# Generated by FakeRAM 2.0
VERSION 5.7 ;
BUSBITCHARS "[]" ;
PROPERTYDEFINITIONS
  MACRO width INTEGER ;
  MACRO depth INTEGER ;
  MACRO banks INTEGER ;
END PROPERTYDEFINITIONS
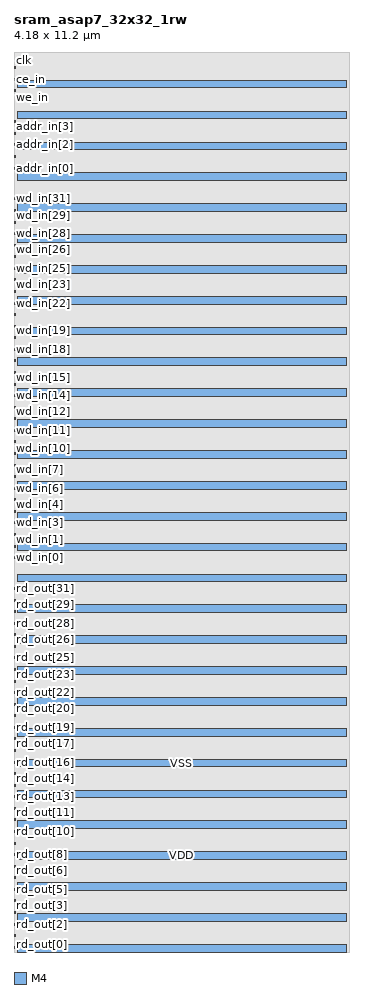
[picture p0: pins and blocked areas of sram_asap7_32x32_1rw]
MACRO sram_asap7_32x32_1rw
  PROPERTY width 32 ;
  PROPERTY depth 32 ;
  PROPERTY banks 1 ;
  FOREIGN sram_asap7_32x32_1rw 0 0 ;
  SYMMETRY X Y R90 ;
  SIZE 4.180 BY 11.200 ;
  CLASS BLOCK ;
  PIN rd_out[0]
    DIRECTION OUTPUT ;
    USE SIGNAL ;
    SHAPE ABUTMENT ;
    PORT
      LAYER M4 ;
      RECT 0.000 0.048 0.024 0.072 ;
    END
  END rd_out[0]
  PIN rd_out[1]
    DIRECTION OUTPUT ;
    USE SIGNAL ;
    SHAPE ABUTMENT ;
    PORT
      LAYER M4 ;
      RECT 0.000 0.192 0.024 0.216 ;
    END
  END rd_out[1]
  PIN rd_out[2]
    DIRECTION OUTPUT ;
    USE SIGNAL ;
    SHAPE ABUTMENT ;
    PORT
      LAYER M4 ;
      RECT 0.000 0.336 0.024 0.360 ;
    END
  END rd_out[2]
  PIN rd_out[3]
    DIRECTION OUTPUT ;
    USE SIGNAL ;
    SHAPE ABUTMENT ;
    PORT
      LAYER M4 ;
      RECT 0.000 0.480 0.024 0.504 ;
    END
  END rd_out[3]
  PIN rd_out[4]
    DIRECTION OUTPUT ;
    USE SIGNAL ;
    SHAPE ABUTMENT ;
    PORT
      LAYER M4 ;
      RECT 0.000 0.624 0.024 0.648 ;
    END
  END rd_out[4]
  PIN rd_out[5]
    DIRECTION OUTPUT ;
    USE SIGNAL ;
    SHAPE ABUTMENT ;
    PORT
      LAYER M4 ;
      RECT 0.000 0.768 0.024 0.792 ;
    END
  END rd_out[5]
  PIN rd_out[6]
    DIRECTION OUTPUT ;
    USE SIGNAL ;
    SHAPE ABUTMENT ;
    PORT
      LAYER M4 ;
      RECT 0.000 0.912 0.024 0.936 ;
    END
  END rd_out[6]
  PIN rd_out[7]
    DIRECTION OUTPUT ;
    USE SIGNAL ;
    SHAPE ABUTMENT ;
    PORT
      LAYER M4 ;
      RECT 0.000 1.056 0.024 1.080 ;
    END
  END rd_out[7]
  PIN rd_out[8]
    DIRECTION OUTPUT ;
    USE SIGNAL ;
    SHAPE ABUTMENT ;
    PORT
      LAYER M4 ;
      RECT 0.000 1.200 0.024 1.224 ;
    END
  END rd_out[8]
  PIN rd_out[9]
    DIRECTION OUTPUT ;
    USE SIGNAL ;
    SHAPE ABUTMENT ;
    PORT
      LAYER M4 ;
      RECT 0.000 1.344 0.024 1.368 ;
    END
  END rd_out[9]
  PIN rd_out[10]
    DIRECTION OUTPUT ;
    USE SIGNAL ;
    SHAPE ABUTMENT ;
    PORT
      LAYER M4 ;
      RECT 0.000 1.488 0.024 1.512 ;
    END
  END rd_out[10]
  PIN rd_out[11]
    DIRECTION OUTPUT ;
    USE SIGNAL ;
    SHAPE ABUTMENT ;
    PORT
      LAYER M4 ;
      RECT 0.000 1.632 0.024 1.656 ;
    END
  END rd_out[11]
  PIN rd_out[12]
    DIRECTION OUTPUT ;
    USE SIGNAL ;
    SHAPE ABUTMENT ;
    PORT
      LAYER M4 ;
      RECT 0.000 1.776 0.024 1.800 ;
    END
  END rd_out[12]
  PIN rd_out[13]
    DIRECTION OUTPUT ;
    USE SIGNAL ;
    SHAPE ABUTMENT ;
    PORT
      LAYER M4 ;
      RECT 0.000 1.920 0.024 1.944 ;
    END
  END rd_out[13]
  PIN rd_out[14]
    DIRECTION OUTPUT ;
    USE SIGNAL ;
    SHAPE ABUTMENT ;
    PORT
      LAYER M4 ;
      RECT 0.000 2.064 0.024 2.088 ;
    END
  END rd_out[14]
  PIN rd_out[15]
    DIRECTION OUTPUT ;
    USE SIGNAL ;
    SHAPE ABUTMENT ;
    PORT
      LAYER M4 ;
      RECT 0.000 2.208 0.024 2.232 ;
    END
  END rd_out[15]
  PIN rd_out[16]
    DIRECTION OUTPUT ;
    USE SIGNAL ;
    SHAPE ABUTMENT ;
    PORT
      LAYER M4 ;
      RECT 0.000 2.352 0.024 2.376 ;
    END
  END rd_out[16]
  PIN rd_out[17]
    DIRECTION OUTPUT ;
    USE SIGNAL ;
    SHAPE ABUTMENT ;
    PORT
      LAYER M4 ;
      RECT 0.000 2.496 0.024 2.520 ;
    END
  END rd_out[17]
  PIN rd_out[18]
    DIRECTION OUTPUT ;
    USE SIGNAL ;
    SHAPE ABUTMENT ;
    PORT
      LAYER M4 ;
      RECT 0.000 2.640 0.024 2.664 ;
    END
  END rd_out[18]
  PIN rd_out[19]
    DIRECTION OUTPUT ;
    USE SIGNAL ;
    SHAPE ABUTMENT ;
    PORT
      LAYER M4 ;
      RECT 0.000 2.784 0.024 2.808 ;
    END
  END rd_out[19]
  PIN rd_out[20]
    DIRECTION OUTPUT ;
    USE SIGNAL ;
    SHAPE ABUTMENT ;
    PORT
      LAYER M4 ;
      RECT 0.000 2.928 0.024 2.952 ;
    END
  END rd_out[20]
  PIN rd_out[21]
    DIRECTION OUTPUT ;
    USE SIGNAL ;
    SHAPE ABUTMENT ;
    PORT
      LAYER M4 ;
      RECT 0.000 3.072 0.024 3.096 ;
    END
  END rd_out[21]
  PIN rd_out[22]
    DIRECTION OUTPUT ;
    USE SIGNAL ;
    SHAPE ABUTMENT ;
    PORT
      LAYER M4 ;
      RECT 0.000 3.216 0.024 3.240 ;
    END
  END rd_out[22]
  PIN rd_out[23]
    DIRECTION OUTPUT ;
    USE SIGNAL ;
    SHAPE ABUTMENT ;
    PORT
      LAYER M4 ;
      RECT 0.000 3.360 0.024 3.384 ;
    END
  END rd_out[23]
  PIN rd_out[24]
    DIRECTION OUTPUT ;
    USE SIGNAL ;
    SHAPE ABUTMENT ;
    PORT
      LAYER M4 ;
      RECT 0.000 3.504 0.024 3.528 ;
    END
  END rd_out[24]
  PIN rd_out[25]
    DIRECTION OUTPUT ;
    USE SIGNAL ;
    SHAPE ABUTMENT ;
    PORT
      LAYER M4 ;
      RECT 0.000 3.648 0.024 3.672 ;
    END
  END rd_out[25]
  PIN rd_out[26]
    DIRECTION OUTPUT ;
    USE SIGNAL ;
    SHAPE ABUTMENT ;
    PORT
      LAYER M4 ;
      RECT 0.000 3.792 0.024 3.816 ;
    END
  END rd_out[26]
  PIN rd_out[27]
    DIRECTION OUTPUT ;
    USE SIGNAL ;
    SHAPE ABUTMENT ;
    PORT
      LAYER M4 ;
      RECT 0.000 3.936 0.024 3.960 ;
    END
  END rd_out[27]
  PIN rd_out[28]
    DIRECTION OUTPUT ;
    USE SIGNAL ;
    SHAPE ABUTMENT ;
    PORT
      LAYER M4 ;
      RECT 0.000 4.080 0.024 4.104 ;
    END
  END rd_out[28]
  PIN rd_out[29]
    DIRECTION OUTPUT ;
    USE SIGNAL ;
    SHAPE ABUTMENT ;
    PORT
      LAYER M4 ;
      RECT 0.000 4.224 0.024 4.248 ;
    END
  END rd_out[29]
  PIN rd_out[30]
    DIRECTION OUTPUT ;
    USE SIGNAL ;
    SHAPE ABUTMENT ;
    PORT
      LAYER M4 ;
      RECT 0.000 4.368 0.024 4.392 ;
    END
  END rd_out[30]
  PIN rd_out[31]
    DIRECTION OUTPUT ;
    USE SIGNAL ;
    SHAPE ABUTMENT ;
    PORT
      LAYER M4 ;
      RECT 0.000 4.512 0.024 4.536 ;
    END
  END rd_out[31]
  PIN wd_in[0]
    DIRECTION INPUT ;
    USE SIGNAL ;
    SHAPE ABUTMENT ;
    PORT
      LAYER M4 ;
      RECT 0.000 4.896 0.024 4.920 ;
    END
  END wd_in[0]
  PIN wd_in[1]
    DIRECTION INPUT ;
    USE SIGNAL ;
    SHAPE ABUTMENT ;
    PORT
      LAYER M4 ;
      RECT 0.000 5.040 0.024 5.064 ;
    END
  END wd_in[1]
  PIN wd_in[2]
    DIRECTION INPUT ;
    USE SIGNAL ;
    SHAPE ABUTMENT ;
    PORT
      LAYER M4 ;
      RECT 0.000 5.184 0.024 5.208 ;
    END
  END wd_in[2]
  PIN wd_in[3]
    DIRECTION INPUT ;
    USE SIGNAL ;
    SHAPE ABUTMENT ;
    PORT
      LAYER M4 ;
      RECT 0.000 5.328 0.024 5.352 ;
    END
  END wd_in[3]
  PIN wd_in[4]
    DIRECTION INPUT ;
    USE SIGNAL ;
    SHAPE ABUTMENT ;
    PORT
      LAYER M4 ;
      RECT 0.000 5.472 0.024 5.496 ;
    END
  END wd_in[4]
  PIN wd_in[5]
    DIRECTION INPUT ;
    USE SIGNAL ;
    SHAPE ABUTMENT ;
    PORT
      LAYER M4 ;
      RECT 0.000 5.616 0.024 5.640 ;
    END
  END wd_in[5]
  PIN wd_in[6]
    DIRECTION INPUT ;
    USE SIGNAL ;
    SHAPE ABUTMENT ;
    PORT
      LAYER M4 ;
      RECT 0.000 5.760 0.024 5.784 ;
    END
  END wd_in[6]
  PIN wd_in[7]
    DIRECTION INPUT ;
    USE SIGNAL ;
    SHAPE ABUTMENT ;
    PORT
      LAYER M4 ;
      RECT 0.000 5.904 0.024 5.928 ;
    END
  END wd_in[7]
  PIN wd_in[8]
    DIRECTION INPUT ;
    USE SIGNAL ;
    SHAPE ABUTMENT ;
    PORT
      LAYER M4 ;
      RECT 0.000 6.048 0.024 6.072 ;
    END
  END wd_in[8]
  PIN wd_in[9]
    DIRECTION INPUT ;
    USE SIGNAL ;
    SHAPE ABUTMENT ;
    PORT
      LAYER M4 ;
      RECT 0.000 6.192 0.024 6.216 ;
    END
  END wd_in[9]
  PIN wd_in[10]
    DIRECTION INPUT ;
    USE SIGNAL ;
    SHAPE ABUTMENT ;
    PORT
      LAYER M4 ;
      RECT 0.000 6.336 0.024 6.360 ;
    END
  END wd_in[10]
  PIN wd_in[11]
    DIRECTION INPUT ;
    USE SIGNAL ;
    SHAPE ABUTMENT ;
    PORT
      LAYER M4 ;
      RECT 0.000 6.480 0.024 6.504 ;
    END
  END wd_in[11]
  PIN wd_in[12]
    DIRECTION INPUT ;
    USE SIGNAL ;
    SHAPE ABUTMENT ;
    PORT
      LAYER M4 ;
      RECT 0.000 6.624 0.024 6.648 ;
    END
  END wd_in[12]
  PIN wd_in[13]
    DIRECTION INPUT ;
    USE SIGNAL ;
    SHAPE ABUTMENT ;
    PORT
      LAYER M4 ;
      RECT 0.000 6.768 0.024 6.792 ;
    END
  END wd_in[13]
  PIN wd_in[14]
    DIRECTION INPUT ;
    USE SIGNAL ;
    SHAPE ABUTMENT ;
    PORT
      LAYER M4 ;
      RECT 0.000 6.912 0.024 6.936 ;
    END
  END wd_in[14]
  PIN wd_in[15]
    DIRECTION INPUT ;
    USE SIGNAL ;
    SHAPE ABUTMENT ;
    PORT
      LAYER M4 ;
      RECT 0.000 7.056 0.024 7.080 ;
    END
  END wd_in[15]
  PIN wd_in[16]
    DIRECTION INPUT ;
    USE SIGNAL ;
    SHAPE ABUTMENT ;
    PORT
      LAYER M4 ;
      RECT 0.000 7.200 0.024 7.224 ;
    END
  END wd_in[16]
  PIN wd_in[17]
    DIRECTION INPUT ;
    USE SIGNAL ;
    SHAPE ABUTMENT ;
    PORT
      LAYER M4 ;
      RECT 0.000 7.344 0.024 7.368 ;
    END
  END wd_in[17]
  PIN wd_in[18]
    DIRECTION INPUT ;
    USE SIGNAL ;
    SHAPE ABUTMENT ;
    PORT
      LAYER M4 ;
      RECT 0.000 7.488 0.024 7.512 ;
    END
  END wd_in[18]
  PIN wd_in[19]
    DIRECTION INPUT ;
    USE SIGNAL ;
    SHAPE ABUTMENT ;
    PORT
      LAYER M4 ;
      RECT 0.000 7.632 0.024 7.656 ;
    END
  END wd_in[19]
  PIN wd_in[20]
    DIRECTION INPUT ;
    USE SIGNAL ;
    SHAPE ABUTMENT ;
    PORT
      LAYER M4 ;
      RECT 0.000 7.776 0.024 7.800 ;
    END
  END wd_in[20]
  PIN wd_in[21]
    DIRECTION INPUT ;
    USE SIGNAL ;
    SHAPE ABUTMENT ;
    PORT
      LAYER M4 ;
      RECT 0.000 7.920 0.024 7.944 ;
    END
  END wd_in[21]
  PIN wd_in[22]
    DIRECTION INPUT ;
    USE SIGNAL ;
    SHAPE ABUTMENT ;
    PORT
      LAYER M4 ;
      RECT 0.000 8.064 0.024 8.088 ;
    END
  END wd_in[22]
  PIN wd_in[23]
    DIRECTION INPUT ;
    USE SIGNAL ;
    SHAPE ABUTMENT ;
    PORT
      LAYER M4 ;
      RECT 0.000 8.208 0.024 8.232 ;
    END
  END wd_in[23]
  PIN wd_in[24]
    DIRECTION INPUT ;
    USE SIGNAL ;
    SHAPE ABUTMENT ;
    PORT
      LAYER M4 ;
      RECT 0.000 8.352 0.024 8.376 ;
    END
  END wd_in[24]
  PIN wd_in[25]
    DIRECTION INPUT ;
    USE SIGNAL ;
    SHAPE ABUTMENT ;
    PORT
      LAYER M4 ;
      RECT 0.000 8.496 0.024 8.520 ;
    END
  END wd_in[25]
  PIN wd_in[26]
    DIRECTION INPUT ;
    USE SIGNAL ;
    SHAPE ABUTMENT ;
    PORT
      LAYER M4 ;
      RECT 0.000 8.640 0.024 8.664 ;
    END
  END wd_in[26]
  PIN wd_in[27]
    DIRECTION INPUT ;
    USE SIGNAL ;
    SHAPE ABUTMENT ;
    PORT
      LAYER M4 ;
      RECT 0.000 8.784 0.024 8.808 ;
    END
  END wd_in[27]
  PIN wd_in[28]
    DIRECTION INPUT ;
    USE SIGNAL ;
    SHAPE ABUTMENT ;
    PORT
      LAYER M4 ;
      RECT 0.000 8.928 0.024 8.952 ;
    END
  END wd_in[28]
  PIN wd_in[29]
    DIRECTION INPUT ;
    USE SIGNAL ;
    SHAPE ABUTMENT ;
    PORT
      LAYER M4 ;
      RECT 0.000 9.072 0.024 9.096 ;
    END
  END wd_in[29]
  PIN wd_in[30]
    DIRECTION INPUT ;
    USE SIGNAL ;
    SHAPE ABUTMENT ;
    PORT
      LAYER M4 ;
      RECT 0.000 9.216 0.024 9.240 ;
    END
  END wd_in[30]
  PIN wd_in[31]
    DIRECTION INPUT ;
    USE SIGNAL ;
    SHAPE ABUTMENT ;
    PORT
      LAYER M4 ;
      RECT 0.000 9.360 0.024 9.384 ;
    END
  END wd_in[31]
  PIN addr_in[0]
    DIRECTION INPUT ;
    USE SIGNAL ;
    SHAPE ABUTMENT ;
    PORT
      LAYER M4 ;
      RECT 0.000 9.744 0.024 9.768 ;
    END
  END addr_in[0]
  PIN addr_in[1]
    DIRECTION INPUT ;
    USE SIGNAL ;
    SHAPE ABUTMENT ;
    PORT
      LAYER M4 ;
      RECT 0.000 9.888 0.024 9.912 ;
    END
  END addr_in[1]
  PIN addr_in[2]
    DIRECTION INPUT ;
    USE SIGNAL ;
    SHAPE ABUTMENT ;
    PORT
      LAYER M4 ;
      RECT 0.000 10.032 0.024 10.056 ;
    END
  END addr_in[2]
  PIN addr_in[3]
    DIRECTION INPUT ;
    USE SIGNAL ;
    SHAPE ABUTMENT ;
    PORT
      LAYER M4 ;
      RECT 0.000 10.176 0.024 10.200 ;
    END
  END addr_in[3]
  PIN addr_in[4]
    DIRECTION INPUT ;
    USE SIGNAL ;
    SHAPE ABUTMENT ;
    PORT
      LAYER M4 ;
      RECT 0.000 10.320 0.024 10.344 ;
    END
  END addr_in[4]
  PIN we_in
    DIRECTION INPUT ;
    USE SIGNAL ;
    SHAPE ABUTMENT ;
    PORT
      LAYER M4 ;
      RECT 0.000 10.704 0.024 10.728 ;
    END
  END we_in
  PIN ce_in
    DIRECTION INPUT ;
    USE SIGNAL ;
    SHAPE ABUTMENT ;
    PORT
      LAYER M4 ;
      RECT 0.000 10.848 0.024 10.872 ;
    END
  END ce_in
  PIN clk
    DIRECTION INPUT ;
    USE SIGNAL ;
    SHAPE ABUTMENT ;
    PORT
      LAYER M4 ;
      RECT 0.000 10.992 0.024 11.016 ;
    END
  END clk
  PIN VSS
    DIRECTION INOUT ;
    USE GROUND ;
    PORT
      LAYER M4 ;
      RECT 0.048 0.000 4.132 0.096 ;
      RECT 0.048 0.768 4.132 0.864 ;
      RECT 0.048 1.536 4.132 1.632 ;
      RECT 0.048 2.304 4.132 2.400 ;
      RECT 0.048 3.072 4.132 3.168 ;
      RECT 0.048 3.840 4.132 3.936 ;
      RECT 0.048 4.608 4.132 4.704 ;
      RECT 0.048 5.376 4.132 5.472 ;
      RECT 0.048 6.144 4.132 6.240 ;
      RECT 0.048 6.912 4.132 7.008 ;
      RECT 0.048 7.680 4.132 7.776 ;
      RECT 0.048 8.448 4.132 8.544 ;
      RECT 0.048 9.216 4.132 9.312 ;
      RECT 0.048 9.984 4.132 10.080 ;
      RECT 0.048 10.752 4.132 10.848 ;
    END
  END VSS
  PIN VDD
    DIRECTION INOUT ;
    USE POWER ;
    PORT
      LAYER M4 ;
      RECT 0.048 0.384 4.132 0.480 ;
      RECT 0.048 1.152 4.132 1.248 ;
      RECT 0.048 1.920 4.132 2.016 ;
      RECT 0.048 2.688 4.132 2.784 ;
      RECT 0.048 3.456 4.132 3.552 ;
      RECT 0.048 4.224 4.132 4.320 ;
      RECT 0.048 4.992 4.132 5.088 ;
      RECT 0.048 5.760 4.132 5.856 ;
      RECT 0.048 6.528 4.132 6.624 ;
      RECT 0.048 7.296 4.132 7.392 ;
      RECT 0.048 8.064 4.132 8.160 ;
      RECT 0.048 8.832 4.132 8.928 ;
      RECT 0.048 9.600 4.132 9.696 ;
      RECT 0.048 10.368 4.132 10.464 ;
    END
  END VDD
  OBS
    LAYER M1 ;
    RECT 0 0 4.180 11.200 ;
    LAYER M2 ;
    RECT 0 0 4.180 11.200 ;
    LAYER M3 ;
    RECT 0 0 4.180 11.200 ;
    LAYER M4 ;
    RECT 0 0 4.180 11.200 ;
  END
END sram_asap7_32x32_1rw

END LIBRARY
